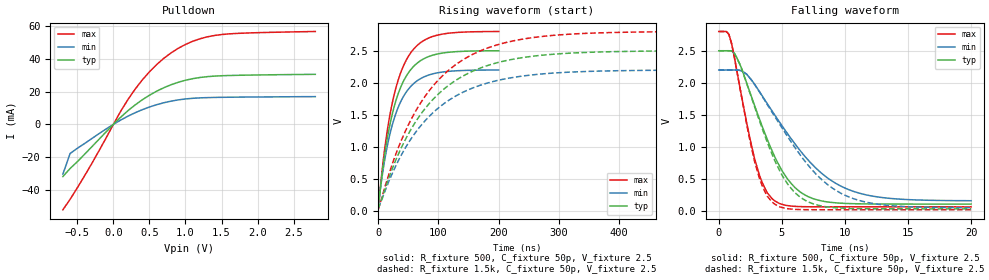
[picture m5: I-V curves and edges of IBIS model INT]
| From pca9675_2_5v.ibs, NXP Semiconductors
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[Model]   INT
Model_type Open_drain
Vref=2.5
Vmeas=1.25
Rref=1.6k
Cref=50p
C_comp   5.2p   5p   5.4p
[Temperature Range] 27   85   -40
[Voltage Range]   2.5   2.2   2.8
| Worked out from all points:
|   slope of the pulldown table from 0 to 0.375 V, typ, clamps not added: 26.5 ohm
|   falling waveform, R_fixture 500, C_fixture 50p, V_fixture 2.5: 20-80 % time 2.99ns typ, 4.82ns min, 1.77ns max; typ from 2.5 V to 0.111 V
|   falling waveform, R_fixture 1.5k, C_fixture 50p, V_fixture 2.5: 20-80 % time 2.93ns typ, 4.7ns min, 1.75ns max; typ from 2.5 V to 0.037 V
|   rising waveform, R_fixture 500, C_fixture 50p, V_fixture 2.5: 20-80 % time 35.2ns typ, 35.2ns min, 35.1ns max; typ from 0.111 V to 2.5 V
|   rising waveform, R_fixture 1.5k, C_fixture 50p, V_fixture 2.5: 20-80 % time 106ns typ, 106ns min, 105ns max; typ from 0.037 V to 2.5 V
[Pulldown]
-700mV    -31.75mA   -30.26mA   -51.97mA
-600mV    -26.85mA   -17.73mA   -45.61mA
-200mV    -9.108mA   -5.667mA   -16.14mA
100mV     4.32mA     2.592mA    7.881mA
300mV     11.78mA    7.059mA    21.34mA
500mV     17.74mA    10.57mA    32mA
600mV     20.2mA     11.99mA    36.4mA
800mV     24.13mA    14.15mA    43.52mA
1.1V      27.83mA    15.88mA    50.58mA
1.4V      29.38mA    16.4mA     54.09mA
1.8V      29.94mA    16.61mA    55.54mA
2.8V      30.47mA    16.91mA    56.54mA
[Falling Waveform]
R_fixture=500
C_fixture=50p
V_fixture=2.5
V_fixture_min=2.2
V_fixture_max=2.8
0s        2.5V       2.2V       2.8V
808.1ps   2.5V       2.2V       2.755V
1.616ns   2.315V     2.198V     1.997V
2.828ns   1.654V     1.982V     827.6mV
3.636ns   1.223V     1.739V     367.6mV
4.444ns   845.3mV    1.497V     161.2mV
6.465ns   298.2mV    941.7mV    71.97mV
10.1ns    120.9mV    352.4mV    68.27mV
13.54ns   111.7mV    200.5mV    68.26mV
20ns      111.2mV    163.5mV    68.26mV
[Falling Waveform]
R_fixture=1.5k
C_fixture=50p
V_fixture=2.5
V_fixture_min=2.2
V_fixture_max=2.8
0s        2.5V       2.2V       2.8V
808.1ps   2.5V       2.2V       2.755V
1.616ns   2.313V     2.198V     1.988V
2.828ns   1.636V     1.979V     785mV
3.636ns   1.186V     1.729V     314.5mV
4.444ns   786.5mV    1.475V     109.3mV
6.465ns   217.1mV    875mV      25.8mV
10.1ns    45.22mV    240.3mV    22.66mV
13.33ns   37.49mV    92.17mV    22.66mV
20ns      37mV       55.35mV    22.66mV
[Rising Waveform]
R_fixture=500
C_fixture=50p
V_fixture=2.5
V_fixture_min=2.2
V_fixture_max=2.8
0s        111.2mV    161.8mV    68.26mV
2.02ns    216.8mV    223.3mV    217.4mV
6.061ns   551.2mV    512.2mV    596.5mV
12.12ns   964mV      868.9mV    1.064V
22.22ns   1.468V     1.305V     1.634V
36.36ns   1.908V     1.686V     2.133V
52.53ns   2.187V     1.928V     2.447V
70.71ns   2.347V     2.067V     2.628V
96.97ns   2.446V     2.153V     2.739V
200ns     2.499V     2.199V     2.799V
[Rising Waveform]
R_fixture=1.5k
C_fixture=50p
V_fixture=2.5
V_fixture_min=2.2
V_fixture_max=2.8
0s        37mV       54.11mV    22.66mV
30.3ns    820.7mV    728.3mV    915mV
48.48ns   1.177V     1.04V      1.315V
66.67ns   1.457V     1.285V     1.631V
84.85ns   1.679V     1.479V     1.88V
109.1ns   1.903V     1.675V     2.131V
157.6ns   2.184V     1.922V     2.446V
212.1ns   2.346V     2.064V     2.628V
290.9ns   2.445V     2.152V     2.739V
600ns     2.499V     2.199V     2.799V
[Ramp]
R_load=1.6k
dV/dt_r   1.479E+0/1.965E-9   1.465E+0/2.160E-9   1.489E+0/1.726E-9
dV/dt_f   1.479E+0/1.846E-10   1.465E+0/3.362E-10   1.489E+0/8.768E-11
|[End   INT
